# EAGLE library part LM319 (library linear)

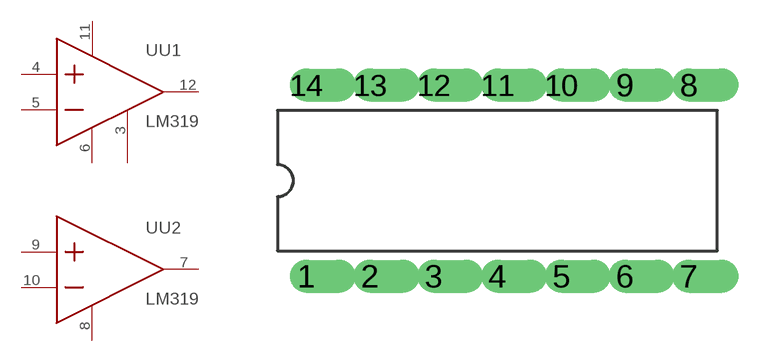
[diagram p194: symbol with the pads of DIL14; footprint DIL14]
Designator prefix -; gates U1=OPAMP+--GND U2=OPAMP&GND

## LM319N  [DIL14]
3  U1:GND
4  U1:+IN
5  U1:-IN
6  U1:VSS
7  U2:OUT2
8  U2:GND2
9  U2:+IN2
10  U2:-IN2
11  U1:VCC
12  U1:OUT

## Footprint DIL14 (pad centres in mm)
DIL
drill 0.813 offset: 1 -7.62,-3.81; 2 -5.08,-3.81; 3 -2.54,-3.81; 4 0,-3.81; 5 2.54,-3.81; 6 5.08,-3.81; 7 7.62,-3.81; 8 7.62,3.81; 9 5.08,3.81; 10 2.54,3.81; 11 0,3.81; 12 -2.54,3.81; 13 -5.08,3.81; 14 -7.62,3.81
